#************************************************************************************************#
# Copyright (C) 2021 by Cadence Design Systems Inc	         	                         #
#************************************************************************************************#
#************************************************************************************************#
# IP               : cdn_sd1000_t16ffc_01_vc176_2xa1xd3xe2y2r                            	 #
# DESCRIPTION      : LEF file  									 #
# CREATED BY       : Sachin Nandurkar (sachinn@cadence.com)       				 #
# LAST CHANGED     : 20210527                                                                    #
# VERSION          : 102                                                                         #
# VERSION HISTORY  : 101 20191024 , File created				 		 #
# VERSION HISTORY  : 102 20210602 , Updated bump pin location				 	 #
# DISCLAIMER       : The lef parser used to verify the syntax of this file may have bugs. Please #
#                  : ensure that there are no problems while you read this file in your tool. 	 #
#************************************************************************************************#

VERSION 5.7 ;
BUSBITCHARS "[]" ;
DIVIDERCHAR "/" ;

SITE SITEOFcdn_sd1000_t16ffc_01_vc176_2xa1xd3xe2y2r
  CLASS CORE ;
  SYMMETRY X Y ;
  SIZE 540 BY 540 ;
END SITEOFcdn_sd1000_t16ffc_01_vc176_2xa1xd3xe2y2r

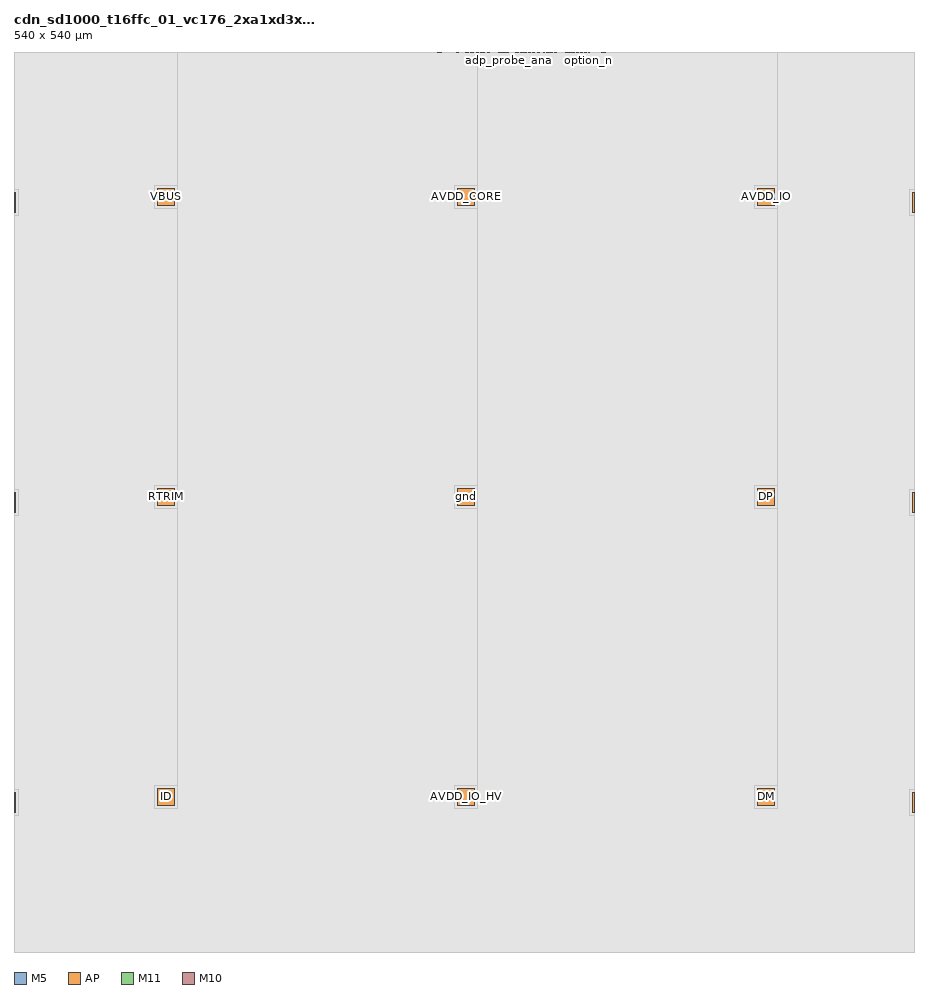
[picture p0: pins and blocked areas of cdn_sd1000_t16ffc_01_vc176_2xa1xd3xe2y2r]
MACRO cdn_sd1000_t16ffc_01_vc176_2xa1xd3xe2y2r
  CLASS BLOCK ;
  ORIGIN 0 0 ;
  FOREIGN cdn_sd1000_t16ffc_01_vc176_2xa1xd3xe2y2r 0 0 ;
  SIZE 540 BY 540 ;
  SYMMETRY X Y ;
  SITE SITEOFcdn_sd1000_t16ffc_01_vc176_2xa1xd3xe2y2r ;
  PIN tap_trst_n
    DIRECTION INPUT ;
    USE SIGNAL ;
    PORT
      LAYER M5 ;
        RECT 321.64 539.8 321.72 540 ;
    END
  END tap_trst_n
  PIN databus_reset
    DIRECTION INPUT ;
    USE SIGNAL ;
    PORT
      LAYER M5 ;
        RECT 305.88 539.8 305.96 540 ;
    END
  END databus_reset
  PIN hssi_tx_clockin
    DIRECTION INPUT ;
    USE SIGNAL ;
    PORT
      LAYER M5 ;
        RECT 265.72 539.8 265.8 540 ;
    END
  END hssi_tx_clockin
  PIN scan_sieclock
    DIRECTION INPUT ;
    USE SIGNAL ;
    PORT
      LAYER M5 ;
        RECT 266.68 539.8 266.76 540 ;
    END
  END scan_sieclock
  PIN psm_clock
    DIRECTION INPUT ;
    USE SIGNAL ;
    PORT
      LAYER M5 ;
        RECT 267.64 539.8 267.72 540 ;
    END
  END psm_clock
  PIN apb_pclk
    DIRECTION INPUT ;
    USE SIGNAL ;
    PORT
      LAYER M5 ;
        RECT 267.32 539.8 267.4 540 ;
    END
  END apb_pclk
  PIN scan_out[22]
    DIRECTION OUTPUT ;
    USE SIGNAL ;
    PORT
      LAYER M5 ;
        RECT 353.08 539.8 353.16 540 ;
    END
  END scan_out[22]
  PIN scan_out[33]
    DIRECTION OUTPUT ;
    USE SIGNAL ;
    PORT
      LAYER M5 ;
        RECT 354.84 539.8 354.92 540 ;
    END
  END scan_out[33]
  PIN scan_out[31]
    DIRECTION OUTPUT ;
    USE SIGNAL ;
    PORT
      LAYER M5 ;
        RECT 354.52 539.8 354.6 540 ;
    END
  END scan_out[31]
  PIN scan_out[29]
    DIRECTION OUTPUT ;
    USE SIGNAL ;
    PORT
      LAYER M5 ;
        RECT 354.2 539.8 354.28 540 ;
    END
  END scan_out[29]
  PIN scan_out[27]
    DIRECTION OUTPUT ;
    USE SIGNAL ;
    PORT
      LAYER M5 ;
        RECT 353.88 539.8 353.96 540 ;
    END
  END scan_out[27]
  PIN scan_out[25]
    DIRECTION OUTPUT ;
    USE SIGNAL ;
    PORT
      LAYER M5 ;
        RECT 353.56 539.8 353.64 540 ;
    END
  END scan_out[25]
  PIN scan_out[23]
    DIRECTION OUTPUT ;
    USE SIGNAL ;
    PORT
      LAYER M5 ;
        RECT 353.24 539.8 353.32 540 ;
    END
  END scan_out[23]
  PIN scan_out[20]
    DIRECTION OUTPUT ;
    USE SIGNAL ;
    PORT
      LAYER M5 ;
        RECT 352.76 539.8 352.84 540 ;
    END
  END scan_out[20]
  PIN scan_out[18]
    DIRECTION OUTPUT ;
    USE SIGNAL ;
    PORT
      LAYER M5 ;
        RECT 352.44 539.8 352.52 540 ;
    END
  END scan_out[18]
  PIN scan_in[18]
    DIRECTION INPUT ;
    USE SIGNAL ;
    PORT
      LAYER M5 ;
        RECT 279.32 539.8 279.4 540 ;
    END
  END scan_in[18]
  PIN scan_in[20]
    DIRECTION INPUT ;
    USE SIGNAL ;
    PORT
      LAYER M5 ;
        RECT 279.64 539.8 279.72 540 ;
    END
  END scan_in[20]
  PIN scan_in[22]
    DIRECTION INPUT ;
    USE SIGNAL ;
    PORT
      LAYER M5 ;
        RECT 279.96 539.8 280.04 540 ;
    END
  END scan_in[22]
  PIN adp_sense_ana
    DIRECTION OUTPUT ;
    USE SIGNAL ;
    PORT
      LAYER M5 ;
        RECT 296.52 539.8 296.6 540 ;
    END
  END adp_sense_ana
  PIN sessvld
    DIRECTION OUTPUT ;
    USE SIGNAL ;
    PORT
      LAYER M5 ;
        RECT 296.84 539.8 296.92 540 ;
    END
  END sessvld
  PIN iddig
    DIRECTION OUTPUT ;
    USE SIGNAL ;
    PORT
      LAYER M5 ;
        RECT 303.96 539.8 304.04 540 ;
    END
  END iddig
  PIN hssi_ded_ana
    DIRECTION OUTPUT ;
    USE SIGNAL ;
    PORT
      LAYER M5 ;
        RECT 304.12 539.8 304.2 540 ;
    END
  END hssi_ded_ana
  PIN hssi_squelch
    DIRECTION OUTPUT ;
    USE SIGNAL ;
    PORT
      LAYER M5 ;
        RECT 318.44 539.8 318.52 540 ;
    END
  END hssi_squelch
  PIN hssi_dataout[0]
    DIRECTION OUTPUT ;
    USE SIGNAL ;
    PORT
      LAYER M5 ;
        RECT 337.56 539.8 337.64 540 ;
    END
  END hssi_dataout[0]
  PIN hssi_dataout[2]
    DIRECTION OUTPUT ;
    USE SIGNAL ;
    PORT
      LAYER M5 ;
        RECT 337.88 539.8 337.96 540 ;
    END
  END hssi_dataout[2]
  PIN rx_rcv
    DIRECTION OUTPUT ;
    USE SIGNAL ;
    PORT
      LAYER M5 ;
        RECT 325.48 539.8 325.56 540 ;
    END
  END rx_rcv
  PIN rx_dm
    DIRECTION OUTPUT ;
    USE SIGNAL ;
    PORT
      LAYER M5 ;
        RECT 304.44 539.8 304.52 540 ;
    END
  END rx_dm
  PIN dataout[1]
    DIRECTION OUTPUT ;
    USE SIGNAL ;
    PORT
      LAYER M5 ;
        RECT 335.16 539.8 335.24 540 ;
    END
  END dataout[1]
  PIN datain[6]
    DIRECTION INPUT ;
    USE SIGNAL ;
    PORT
      LAYER M5 ;
        RECT 292.36 539.8 292.44 540 ;
    END
  END datain[6]
  PIN datain[8]
    DIRECTION INPUT ;
    USE SIGNAL ;
    PORT
      LAYER M5 ;
        RECT 292.68 539.8 292.76 540 ;
    END
  END datain[8]
  PIN dp_vdat_ref_comp_en
    DIRECTION INPUT ;
    USE SIGNAL ;
    PORT
      LAYER M5 ;
        RECT 310.84 539.8 310.92 540 ;
    END
  END dp_vdat_ref_comp_en
  PIN scan_in[34]
    DIRECTION INPUT ;
    USE SIGNAL ;
    PORT
      LAYER M5 ;
        RECT 281.88 539.8 281.96 540 ;
    END
  END scan_in[34]
  PIN usb2_phy_spare_out[7]
    DIRECTION OUTPUT ;
    USE SIGNAL ;
    PORT
      LAYER M5 ;
        RECT 340.6 539.8 340.68 540 ;
    END
  END usb2_phy_spare_out[7]
  PIN apb_pready
    DIRECTION OUTPUT ;
    USE SIGNAL ;
    PORT
      LAYER M5 ;
        RECT 306.2 539.8 306.28 540 ;
    END
  END apb_pready
  PIN usb2_phy_spare_out[1]
    DIRECTION OUTPUT ;
    USE SIGNAL ;
    PORT
      LAYER M5 ;
        RECT 339.64 539.8 339.72 540 ;
    END
  END usb2_phy_spare_out[1]
  PIN usb2_phy_spare_out[5]
    DIRECTION OUTPUT ;
    USE SIGNAL ;
    PORT
      LAYER M5 ;
        RECT 340.28 539.8 340.36 540 ;
    END
  END usb2_phy_spare_out[5]
  PIN dm_vdat_ref_comp_en
    DIRECTION INPUT ;
    USE SIGNAL ;
    PORT
      LAYER M5 ;
        RECT 324.36 539.8 324.44 540 ;
    END
  END dm_vdat_ref_comp_en
  PIN usb2_phy_spare_out[3]
    DIRECTION OUTPUT ;
    USE SIGNAL ;
    PORT
      LAYER M5 ;
        RECT 339.96 539.8 340.04 540 ;
    END
  END usb2_phy_spare_out[3]
  PIN scan_in[17]
    DIRECTION INPUT ;
    USE SIGNAL ;
    PORT
      LAYER M5 ;
        RECT 279.16 539.8 279.24 540 ;
    END
  END scan_in[17]
  PIN bist_mode_sel[0]
    DIRECTION INPUT ;
    USE SIGNAL ;
    PORT
      LAYER M5 ;
        RECT 333.08 539.8 333.16 540 ;
    END
  END bist_mode_sel[0]
  PIN scan_in[14]
    DIRECTION INPUT ;
    USE SIGNAL ;
    PORT
      LAYER M5 ;
        RECT 278.68 539.8 278.76 540 ;
    END
  END scan_in[14]
  PIN scan_en
    DIRECTION INPUT ;
    USE SIGNAL ;
    PORT
      LAYER M5 ;
        RECT 309.4 539.8 309.48 540 ;
    END
  END scan_en
  PIN dataout[11]
    DIRECTION OUTPUT ;
    USE SIGNAL ;
    PORT
      LAYER M5 ;
        RECT 336.76 539.8 336.84 540 ;
    END
  END dataout[11]
  PIN dataout[9]
    DIRECTION OUTPUT ;
    USE SIGNAL ;
    PORT
      LAYER M5 ;
        RECT 336.44 539.8 336.52 540 ;
    END
  END dataout[9]
  PIN apb_presetn
    DIRECTION INPUT ;
    USE SIGNAL ;
    PORT
      LAYER M5 ;
        RECT 321.48 539.8 321.56 540 ;
    END
  END apb_presetn
  PIN iddq_mode
    DIRECTION INPUT ;
    USE SIGNAL ;
    PORT
      LAYER M5 ;
        RECT 310.04 539.8 310.12 540 ;
    END
  END iddq_mode
  PIN scan_clock
    DIRECTION INPUT ;
    USE SIGNAL ;
    PORT
      LAYER M5 ;
        RECT 267.96 539.8 268.04 540 ;
    END
  END scan_clock
  PIN tx_se0
    DIRECTION INPUT ;
    USE SIGNAL ;
    PORT
      LAYER M5 ;
        RECT 323.24 539.8 323.32 540 ;
    END
  END tx_se0
  PIN dataout[13]
    DIRECTION OUTPUT ;
    USE SIGNAL ;
    PORT
      LAYER M5 ;
        RECT 337.08 539.8 337.16 540 ;
    END
  END dataout[13]
  PIN dataout[15]
    DIRECTION OUTPUT ;
    USE SIGNAL ;
    PORT
      LAYER M5 ;
        RECT 337.4 539.8 337.48 540 ;
    END
  END dataout[15]
  PIN rxvalid
    DIRECTION OUTPUT ;
    USE SIGNAL ;
    PORT
      LAYER M5 ;
        RECT 319.24 539.8 319.32 540 ;
    END
  END rxvalid
  PIN rxactive
    DIRECTION OUTPUT ;
    USE SIGNAL ;
    PORT
      LAYER M5 ;
        RECT 307.16 539.8 307.24 540 ;
    END
  END rxactive
  PIN linestate[0]
    DIRECTION OUTPUT ;
    USE SIGNAL ;
    PORT
      LAYER M5 ;
        RECT 305.4 539.8 305.48 540 ;
    END
  END linestate[0]
  PIN hostdisconnect
    DIRECTION OUTPUT ;
    USE SIGNAL ;
    PORT
      LAYER M5 ;
        RECT 305.72 539.8 305.8 540 ;
    END
  END hostdisconnect
  PIN scan_out[1]
    DIRECTION OUTPUT ;
    USE SIGNAL ;
    PORT
      LAYER M5 ;
        RECT 340.92 539.8 341 540 ;
    END
  END scan_out[1]
  PIN scan_out[3]
    DIRECTION OUTPUT ;
    USE SIGNAL ;
    PORT
      LAYER M5 ;
        RECT 341.24 539.8 341.32 540 ;
    END
  END scan_out[3]
  PIN scan_out[5]
    DIRECTION OUTPUT ;
    USE SIGNAL ;
    PORT
      LAYER M5 ;
        RECT 341.56 539.8 341.64 540 ;
    END
  END scan_out[5]
  PIN scan_out[7]
    DIRECTION OUTPUT ;
    USE SIGNAL ;
    PORT
      LAYER M5 ;
        RECT 341.88 539.8 341.96 540 ;
    END
  END scan_out[7]
  PIN scan_out[9]
    DIRECTION OUTPUT ;
    USE SIGNAL ;
    PORT
      LAYER M5 ;
        RECT 342.2 539.8 342.28 540 ;
    END
  END scan_out[9]
  PIN scan_out[11]
    DIRECTION OUTPUT ;
    USE SIGNAL ;
    PORT
      LAYER M5 ;
        RECT 342.52 539.8 342.6 540 ;
    END
  END scan_out[11]
  PIN scan_out[13]
    DIRECTION OUTPUT ;
    USE SIGNAL ;
    PORT
      LAYER M5 ;
        RECT 342.84 539.8 342.92 540 ;
    END
  END scan_out[13]
  PIN hssi_rx_clockout
    DIRECTION OUTPUT ;
    USE SIGNAL ;
    PORT
      LAYER M5 ;
        RECT 269.24 539.8 269.32 540 ;
    END
  END hssi_rx_clockout
  PIN pll_clockout
    DIRECTION OUTPUT ;
    USE SIGNAL ;
    PORT
      LAYER M5 ;
        RECT 268.92 539.8 269 540 ;
    END
  END pll_clockout
  PIN scan_ats_sieclock
    DIRECTION OUTPUT ;
    USE SIGNAL ;
    PORT
      LAYER M5 ;
        RECT 265.08 539.8 265.16 540 ;
    END
  END scan_ats_sieclock
  PIN tx_dat
    DIRECTION INPUT ;
    USE SIGNAL ;
    PORT
      LAYER M5 ;
        RECT 319.4 539.8 319.48 540 ;
    END
  END tx_dat
  PIN refclock
    DIRECTION INPUT ;
    USE SIGNAL ;
    PORT
      LAYER M5 ;
        RECT 266.04 539.8 266.12 540 ;
    END
  END refclock
  PIN tap_tck
    DIRECTION INPUT ;
    USE SIGNAL ;
    PORT
      LAYER M5 ;
        RECT 306.04 539.8 306.12 540 ;
    END
  END tap_tck
  PIN scan_hsclock
    DIRECTION INPUT ;
    USE SIGNAL ;
    PORT
      LAYER M5 ;
        RECT 267 539.8 267.08 540 ;
    END
  END scan_hsclock
  PIN datain[0]
    DIRECTION INPUT ;
    USE SIGNAL ;
    PORT
      LAYER M5 ;
        RECT 291.4 539.8 291.48 540 ;
    END
  END datain[0]
  PIN datain[2]
    DIRECTION INPUT ;
    USE SIGNAL ;
    PORT
      LAYER M5 ;
        RECT 291.72 539.8 291.8 540 ;
    END
  END datain[2]
  PIN datain[4]
    DIRECTION INPUT ;
    USE SIGNAL ;
    PORT
      LAYER M5 ;
        RECT 292.04 539.8 292.12 540 ;
    END
  END datain[4]
  PIN bist_complete
    DIRECTION OUTPUT ;
    USE SIGNAL ;
    PORT
      LAYER M5 ;
        RECT 295.72 539.8 295.8 540 ;
    END
  END bist_complete
  PIN rid_float_comp_sts
    DIRECTION OUTPUT ;
    USE SIGNAL ;
    PORT
      LAYER M5 ;
        RECT 295.88 539.8 295.96 540 ;
    END
  END rid_float_comp_sts
  PIN rid_b_comp_sts
    DIRECTION OUTPUT ;
    USE SIGNAL ;
    PORT
      LAYER M5 ;
        RECT 306.52 539.8 306.6 540 ;
    END
  END rid_b_comp_sts
  PIN dp_vdat_ref_comp_sts
    DIRECTION OUTPUT ;
    USE SIGNAL ;
    PORT
      LAYER M5 ;
        RECT 296.2 539.8 296.28 540 ;
    END
  END dp_vdat_ref_comp_sts
  PIN dm_vdat_ref_comp_sts
    DIRECTION OUTPUT ;
    USE SIGNAL ;
    PORT
      LAYER M5 ;
        RECT 296.36 539.8 296.44 540 ;
    END
  END dm_vdat_ref_comp_sts
  PIN pll_clk_sel[1]
    DIRECTION INPUT ;
    USE SIGNAL ;
    PORT
      LAYER M5 ;
        RECT 266.36 539.8 266.44 540 ;
    END
  END pll_clk_sel[1]
  PIN option_cv
    DIRECTION INPUT ;
    USE SIGNAL ;
    PORT
      LAYER M5 ;
        RECT 345.08 539.8 345.16 540 ;
    END
  END option_cv
  PIN tap_tms
    DIRECTION INPUT ;
    USE SIGNAL ;
    PORT
      LAYER M5 ;
        RECT 309.72 539.8 309.8 540 ;
    END
  END tap_tms
  PIN apb_pwdata[0]
    DIRECTION INPUT ;
    USE SIGNAL ;
    PORT
      LAYER M5 ;
        RECT 333.72 539.8 333.8 540 ;
    END
  END apb_pwdata[0]
  PIN apb_pwdata[2]
    DIRECTION INPUT ;
    USE SIGNAL ;
    PORT
      LAYER M5 ;
        RECT 334.04 539.8 334.12 540 ;
    END
  END apb_pwdata[2]
  PIN apb_pwdata[4]
    DIRECTION INPUT ;
    USE SIGNAL ;
    PORT
      LAYER M5 ;
        RECT 334.36 539.8 334.44 540 ;
    END
  END apb_pwdata[4]
  PIN apb_pwdata[6]
    DIRECTION INPUT ;
    USE SIGNAL ;
    PORT
      LAYER M5 ;
        RECT 334.68 539.8 334.76 540 ;
    END
  END apb_pwdata[6]
  PIN apb_paddr[0]
    DIRECTION INPUT ;
    USE SIGNAL ;
    PORT
      LAYER M5 ;
        RECT 332.92 539.8 333 540 ;
    END
  END apb_paddr[0]
  PIN scan_out[16]
    DIRECTION OUTPUT ;
    USE SIGNAL ;
    PORT
      LAYER M5 ;
        RECT 343.32 539.8 343.4 540 ;
    END
  END scan_out[16]
  PIN datain[14]
    DIRECTION INPUT ;
    USE SIGNAL ;
    PORT
      LAYER M5 ;
        RECT 293.64 539.8 293.72 540 ;
    END
  END datain[14]
  PIN usb2_phy_spare_out[6]
    DIRECTION OUTPUT ;
    USE SIGNAL ;
    PORT
      LAYER M5 ;
        RECT 340.44 539.8 340.52 540 ;
    END
  END usb2_phy_spare_out[6]
  PIN bist_error_count[0]
    DIRECTION OUTPUT ;
    USE SIGNAL ;
    PORT
      LAYER M5 ;
        RECT 338.2 539.8 338.28 540 ;
    END
  END bist_error_count[0]
  PIN bist_error_count[2]
    DIRECTION OUTPUT ;
    USE SIGNAL ;
    PORT
      LAYER M5 ;
        RECT 338.52 539.8 338.6 540 ;
    END
  END bist_error_count[2]
  PIN bist_error_count[4]
    DIRECTION OUTPUT ;
    USE SIGNAL ;
    PORT
      LAYER M5 ;
        RECT 338.84 539.8 338.92 540 ;
    END
  END bist_error_count[4]
  PIN bist_error_count[6]
    DIRECTION OUTPUT ;
    USE SIGNAL ;
    PORT
      LAYER M5 ;
        RECT 339.16 539.8 339.24 540 ;
    END
  END bist_error_count[6]
  PIN bist_error
    DIRECTION OUTPUT ;
    USE SIGNAL ;
    PORT
      LAYER M5 ;
        RECT 310.52 539.8 310.6 540 ;
    END
  END bist_error
  PIN rid_gnd_comp_sts
    DIRECTION OUTPUT ;
    USE SIGNAL ;
    PORT
      LAYER M5 ;
        RECT 306.36 539.8 306.44 540 ;
    END
  END rid_gnd_comp_sts
  PIN rid_c_comp_sts
    DIRECTION OUTPUT ;
    USE SIGNAL ;
    PORT
      LAYER M5 ;
        RECT 325.64 539.8 325.72 540 ;
    END
  END rid_c_comp_sts
  PIN rid_a_comp_sts
    DIRECTION OUTPUT ;
    USE SIGNAL ;
    PORT
      LAYER M5 ;
        RECT 296.04 539.8 296.12 540 ;
    END
  END rid_a_comp_sts
  PIN dm_vlgc_comp_sts
    DIRECTION OUTPUT ;
    USE SIGNAL ;
    PORT
      LAYER M5 ;
        RECT 306.68 539.8 306.76 540 ;
    END
  END dm_vlgc_comp_sts
  PIN dcd_comp_sts
    DIRECTION OUTPUT ;
    USE SIGNAL ;
    PORT
      LAYER M5 ;
        RECT 306.84 539.8 306.92 540 ;
    END
  END dcd_comp_sts
  PIN adp_probe_ana
    DIRECTION OUTPUT ;
    USE SIGNAL ;
    PORT
      LAYER M5 ;
        RECT 296.68 539.8 296.76 540 ;
    END
  END adp_probe_ana
  PIN vbusvalid
    DIRECTION OUTPUT ;
    USE SIGNAL ;
    PORT
      LAYER M5 ;
        RECT 297 539.8 297.08 540 ;
    END
  END vbusvalid
  PIN hssi_chirp_data
    DIRECTION OUTPUT ;
    USE SIGNAL ;
    PORT
      LAYER M5 ;
        RECT 317.96 539.8 318.04 540 ;
    END
  END hssi_chirp_data
  PIN hssi_rxerror
    DIRECTION OUTPUT ;
    USE SIGNAL ;
    PORT
      LAYER M5 ;
        RECT 307 539.8 307.08 540 ;
    END
  END hssi_rxerror
  PIN hssi_rxvalid
    DIRECTION OUTPUT ;
    USE SIGNAL ;
    PORT
      LAYER M5 ;
        RECT 304.28 539.8 304.36 540 ;
    END
  END hssi_rxvalid
  PIN hssi_dataout[1]
    DIRECTION OUTPUT ;
    USE SIGNAL ;
    PORT
      LAYER M5 ;
        RECT 337.72 539.8 337.8 540 ;
    END
  END hssi_dataout[1]
  PIN hssi_dataout[3]
    DIRECTION OUTPUT ;
    USE SIGNAL ;
    PORT
      LAYER M5 ;
        RECT 338.04 539.8 338.12 540 ;
    END
  END hssi_dataout[3]
  PIN rx_dp
    DIRECTION OUTPUT ;
    USE SIGNAL ;
    PORT
      LAYER M5 ;
        RECT 318.92 539.8 319 540 ;
    END
  END rx_dp
  PIN dataout[0]
    DIRECTION OUTPUT ;
    USE SIGNAL ;
    PORT
      LAYER M5 ;
        RECT 335 539.8 335.08 540 ;
    END
  END dataout[0]
  PIN dataout[2]
    DIRECTION OUTPUT ;
    USE SIGNAL ;
    PORT
      LAYER M5 ;
        RECT 335.32 539.8 335.4 540 ;
    END
  END dataout[2]
  PIN dataout[4]
    DIRECTION OUTPUT ;
    USE SIGNAL ;
    PORT
      LAYER M5 ;
        RECT 335.64 539.8 335.72 540 ;
    END
  END dataout[4]
  PIN dataout[6]
    DIRECTION OUTPUT ;
    USE SIGNAL ;
    PORT
      LAYER M5 ;
        RECT 335.96 539.8 336.04 540 ;
    END
  END dataout[6]
  PIN dataout[8]
    DIRECTION OUTPUT ;
    USE SIGNAL ;
    PORT
      LAYER M5 ;
        RECT 336.28 539.8 336.36 540 ;
    END
  END dataout[8]
  PIN dataout[10]
    DIRECTION OUTPUT ;
    USE SIGNAL ;
    PORT
      LAYER M5 ;
        RECT 336.6 539.8 336.68 540 ;
    END
  END dataout[10]
  PIN dataout[12]
    DIRECTION OUTPUT ;
    USE SIGNAL ;
    PORT
      LAYER M5 ;
        RECT 336.92 539.8 337 540 ;
    END
  END dataout[12]
  PIN dataout[14]
    DIRECTION OUTPUT ;
    USE SIGNAL ;
    PORT
      LAYER M5 ;
        RECT 337.24 539.8 337.32 540 ;
    END
  END dataout[14]
  PIN rxvalidh
    DIRECTION OUTPUT ;
    USE SIGNAL ;
    PORT
      LAYER M5 ;
        RECT 325.32 539.8 325.4 540 ;
    END
  END rxvalidh
  PIN rxerror
    DIRECTION OUTPUT ;
    USE SIGNAL ;
    PORT
      LAYER M5 ;
        RECT 304.92 539.8 305 540 ;
    END
  END rxerror
  PIN txready
    DIRECTION OUTPUT ;
    USE SIGNAL ;
    PORT
      LAYER M5 ;
        RECT 305.24 539.8 305.32 540 ;
    END
  END txready
  PIN linestate[1]
    DIRECTION OUTPUT ;
    USE SIGNAL ;
    PORT
      LAYER M5 ;
        RECT 305.56 539.8 305.64 540 ;
    END
  END linestate[1]
  PIN scan_out[0]
    DIRECTION OUTPUT ;
    USE SIGNAL ;
    PORT
      LAYER M5 ;
        RECT 340.76 539.8 340.84 540 ;
    END
  END scan_out[0]
  PIN scan_out[2]
    DIRECTION OUTPUT ;
    USE SIGNAL ;
    PORT
      LAYER M5 ;
        RECT 341.08 539.8 341.16 540 ;
    END
  END scan_out[2]
  PIN scan_out[4]
    DIRECTION OUTPUT ;
    USE SIGNAL ;
    PORT
      LAYER M5 ;
        RECT 341.4 539.8 341.48 540 ;
    END
  END scan_out[4]
  PIN scan_out[6]
    DIRECTION OUTPUT ;
    USE SIGNAL ;
    PORT
      LAYER M5 ;
        RECT 341.72 539.8 341.8 540 ;
    END
  END scan_out[6]
  PIN scan_out[8]
    DIRECTION OUTPUT ;
    USE SIGNAL ;
    PORT
      LAYER M5 ;
        RECT 342.04 539.8 342.12 540 ;
    END
  END scan_out[8]
  PIN scan_out[10]
    DIRECTION OUTPUT ;
    USE SIGNAL ;
    PORT
      LAYER M5 ;
        RECT 342.36 539.8 342.44 540 ;
    END
  END scan_out[10]
  PIN scan_out[12]
    DIRECTION OUTPUT ;
    USE SIGNAL ;
    PORT
      LAYER M5 ;
        RECT 342.68 539.8 342.76 540 ;
    END
  END scan_out[12]
  PIN scan_out[14]
    DIRECTION OUTPUT ;
    USE SIGNAL ;
    PORT
      LAYER M5 ;
        RECT 343 539.8 343.08 540 ;
    END
  END scan_out[14]
  PIN hssi_tx_clockout
    DIRECTION OUTPUT ;
    USE SIGNAL ;
    PORT
      LAYER M5 ;
        RECT 264.76 539.8 264.84 540 ;
    END
  END hssi_tx_clockout
  PIN sieclock
    DIRECTION OUTPUT ;
    USE SIGNAL ;
    PORT
      LAYER M5 ;
        RECT 268.6 539.8 268.68 540 ;
    END
  END sieclock
  PIN scan_ats_hsclock
    DIRECTION OUTPUT ;
    USE SIGNAL ;
    PORT
      LAYER M5 ;
        RECT 265.4 539.8 265.48 540 ;
    END
  END scan_ats_hsclock
  PIN option_n
    DIRECTION INPUT ;
    USE SIGNAL ;
    PORT
      LAYER M5 ;
        RECT 344.92 539.8 345 540 ;
    END
  END option_n
  PIN tap_tdi
    DIRECTION INPUT ;
    USE SIGNAL ;
    PORT
      LAYER M5 ;
        RECT 307.32 539.8 307.4 540 ;
    END
  END tap_tdi
  PIN apb_pwdata[1]
    DIRECTION INPUT ;
    USE SIGNAL ;
    PORT
      LAYER M5 ;
        RECT 333.88 539.8 333.96 540 ;
    END
  END apb_pwdata[1]
  PIN apb_pwdata[3]
    DIRECTION INPUT ;
    USE SIGNAL ;
    PORT
      LAYER M5 ;
        RECT 334.2 539.8 334.28 540 ;
    END
  END apb_pwdata[3]
  PIN apb_pwdata[5]
    DIRECTION INPUT ;
    USE SIGNAL ;
    PORT
      LAYER M5 ;
        RECT 334.52 539.8 334.6 540 ;
    END
  END apb_pwdata[5]
  PIN apb_pwdata[7]
    DIRECTION INPUT ;
    USE SIGNAL ;
    PORT
      LAYER M5 ;
        RECT 334.84 539.8 334.92 540 ;
    END
  END apb_pwdata[7]
  PIN apb_paddr[1]
    DIRECTION INPUT ;
    USE SIGNAL ;
    PORT
      LAYER M5 ;
        RECT 332.76 539.8 332.84 540 ;
    END
  END apb_paddr[1]
  PIN apb_paddr[2]
    DIRECTION INPUT ;
    USE SIGNAL ;
    PORT
      LAYER M5 ;
        RECT 332.6 539.8 332.68 540 ;
    END
  END apb_paddr[2]
  PIN scan_in[15]
    DIRECTION INPUT ;
    USE SIGNAL ;
    PORT
      LAYER M5 ;
        RECT 278.84 539.8 278.92 540 ;
    END
  END scan_in[15]
  PIN scan_en_cg
    DIRECTION INPUT ;
    USE SIGNAL ;
    PORT
      LAYER M5 ;
        RECT 282.04 539.8 282.12 540 ;
    END
  END scan_en_cg
  PIN tap_tdoen
    DIRECTION OUTPUT ;
    USE SIGNAL ;
    PORT
      LAYER M5 ;
        RECT 295.24 539.8 295.32 540 ;
    END
  END tap_tdoen
  PIN apb_prdata[0]
    DIRECTION OUTPUT ;
    USE SIGNAL ;
    PORT
      LAYER M5 ;
        RECT 343.48 539.8 343.56 540 ;
    END
  END apb_prdata[0]
  PIN apb_prdata[2]
    DIRECTION OUTPUT ;
    USE SIGNAL ;
    PORT
      LAYER M5 ;
        RECT 343.8 539.8 343.88 540 ;
    END
  END apb_prdata[2]
  PIN apb_prdata[4]
    DIRECTION OUTPUT ;
    USE SIGNAL ;
    PORT
      LAYER M5 ;
        RECT 344.12 539.8 344.2 540 ;
    END
  END apb_prdata[4]
  PIN apb_prdata[6]
    DIRECTION OUTPUT ;
    USE SIGNAL ;
    PORT
      LAYER M5 ;
        RECT 344.44 539.8 344.52 540 ;
    END
  END apb_prdata[6]
  PIN apb_paddr[4]
    DIRECTION INPUT ;
    USE SIGNAL ;
    PORT
      LAYER M5 ;
        RECT 332.28 539.8 332.36 540 ;
    END
  END apb_paddr[4]
  PIN apb_paddr[6]
    DIRECTION INPUT ;
    USE SIGNAL ;
    PORT
      LAYER M5 ;
        RECT 331.96 539.8 332.04 540 ;
    END
  END apb_paddr[6]
  PIN usb2_phy_irq
    DIRECTION OUTPUT ;
    USE SIGNAL ;
    PORT
      LAYER M5 ;
        RECT 345.24 539.8 345.32 540 ;
    END
  END usb2_phy_irq
  PIN apb_penable
    DIRECTION INPUT ;
    USE SIGNAL ;
    PORT
      LAYER M5 ;
        RECT 325.16 539.8 325.24 540 ;
    END
  END apb_penable
  PIN usb2_phy_spare_in[0]
    DIRECTION INPUT ;
    USE SIGNAL ;
    PORT
      LAYER M5 ;
        RECT 293.96 539.8 294.04 540 ;
    END
  END usb2_phy_spare_in[0]
  PIN usb2_phy_spare_in[2]
    DIRECTION INPUT ;
    USE SIGNAL ;
    PORT
      LAYER M5 ;
        RECT 294.28 539.8 294.36 540 ;
    END
  END usb2_phy_spare_in[2]
  PIN usb2_phy_spare_in[4]
    DIRECTION INPUT ;
    USE SIGNAL ;
    PORT
      LAYER M5 ;
        RECT 294.6 539.8 294.68 540 ;
    END
  END usb2_phy_spare_in[4]
  PIN usb2_phy_spare_in[6]
    DIRECTION INPUT ;
    USE SIGNAL ;
    PORT
      LAYER M5 ;
        RECT 294.92 539.8 295 540 ;
    END
  END usb2_phy_spare_in[6]
  PIN loopback[0]
    DIRECTION INPUT ;
    USE SIGNAL ;
    PORT
      LAYER M5 ;
        RECT 325 539.8 325.08 540 ;
    END
  END loopback[0]
  PIN bist_on
    DIRECTION INPUT ;
    USE SIGNAL ;
    PORT
      LAYER M5 ;
        RECT 324.68 539.8 324.76 540 ;
    END
  END bist_on
  PIN bist_mode_sel[1]
    DIRECTION INPUT ;
    USE SIGNAL ;
    PORT
      LAYER M5 ;
        RECT 333.24 539.8 333.32 540 ;
    END
  END bist_mode_sel[1]
  PIN bist_mode_sel[3]
    DIRECTION INPUT ;
    USE SIGNAL ;
    PORT
      LAYER M5 ;
        RECT 333.56 539.8 333.64 540 ;
    END
  END bist_mode_sel[3]
  PIN pll_bypass_mode
    DIRECTION INPUT ;
    USE SIGNAL ;
    PORT
      LAYER M5 ;
        RECT 307.64 539.8 307.72 540 ;
    END
  END pll_bypass_mode
  PIN vdp_src_en
    DIRECTION INPUT ;
    USE SIGNAL ;
    PORT
      LAYER M5 ;
        RECT 307.96 539.8 308.04 540 ;
    END
  END vdp_src_en
  PIN rid_nonfloat_comp_en
    DIRECTION INPUT ;
    USE SIGNAL ;
    PORT
      LAYER M5 ;
        RECT 324.52 539.8 324.6 540 ;
    END
  END rid_nonfloat_comp_en
  PIN idp_src_en
    DIRECTION INPUT ;
    USE SIGNAL ;
    PORT
      LAYER M5 ;
        RECT 295.56 539.8 295.64 540 ;
    END
  END idp_src_en
  PIN idm_sink_en
    DIRECTION INPUT ;
    USE SIGNAL ;
    PORT
      LAYER M5 ;
        RECT 308.12 539.8 308.2 540 ;
    END
  END idm_sink_en
  PIN dm_vlgc_comp_en
    DIRECTION INPUT ;
    USE SIGNAL ;
    PORT
      LAYER M5 ;
        RECT 311 539.8 311.08 540 ;
    END
  END dm_vlgc_comp_en
  PIN bc_en
    DIRECTION INPUT ;
    USE SIGNAL ;
    PORT
      LAYER M5 ;
        RECT 324.2 539.8 324.28 540 ;
    END
  END bc_en
  PIN adp_sink_current_en
    DIRECTION INPUT ;
    USE SIGNAL ;
    PORT
      LAYER M5 ;
        RECT 311.32 539.8 311.4 540 ;
    END
  END adp_sink_current_en
  PIN adp_en
    DIRECTION INPUT ;
    USE SIGNAL ;
    PORT
      LAYER M5 ;
        RECT 311.64 539.8 311.72 540 ;
    END
  END adp_en
  PIN idpullup
    DIRECTION INPUT ;
    USE SIGNAL ;
    PORT
      LAYER M5 ;
        RECT 308.28 539.8 308.36 540 ;
    END
  END idpullup
  PIN vbus_sel[1]
    DIRECTION INPUT ;
    USE SIGNAL ;
    PORT
      LAYER M5 ;
        RECT 321.32 539.8 321.4 540 ;
    END
  END vbus_sel[1]
  PIN pllrefsel[1]
    DIRECTION INPUT ;
    USE SIGNAL ;
    PORT
      LAYER M5 ;
        RECT 321.8 539.8 321.88 540 ;
    END
  END pllrefsel[1]
  PIN pllrefsel[3]
    DIRECTION INPUT ;
    USE SIGNAL ;
    PORT
      LAYER M5 ;
        RECT 322.28 539.8 322.36 540 ;
    END
  END pllrefsel[3]
  PIN pll_standalone
    DIRECTION INPUT ;
    USE SIGNAL ;
    PORT
      LAYER M5 ;
        RECT 308.44 539.8 308.52 540 ;
    END
  END pll_standalone
  PIN pll_clk_sel[0]
    DIRECTION INPUT ;
    USE SIGNAL ;
    PORT
      LAYER M5 ;
        RECT 268.28 539.8 268.36 540 ;
    END
  END pll_clk_sel[0]
  PIN usb2_phy_arch[0]
    DIRECTION INPUT ;
    USE SIGNAL ;
    PORT
      LAYER M5 ;
        RECT 318.28 539.8 318.36 540 ;
    END
  END usb2_phy_arch[0]
  PIN pso_disable_sel[0]
    DIRECTION INPUT ;
    USE SIGNAL ;
    PORT
      LAYER M5 ;
        RECT 304.6 539.8 304.68 540 ;
    END
  END pso_disable_sel[0]
  PIN pso_disable
    DIRECTION INPUT ;
    USE SIGNAL ;
    PORT
      LAYER M5 ;
        RECT 318.6 539.8 318.68 540 ;
    END
  END pso_disable
  PIN hssi_tx_enable
    DIRECTION INPUT ;
    USE SIGNAL ;
    PORT
      LAYER M5 ;
        RECT 318.76 539.8 318.84 540 ;
    END
  END hssi_tx_enable
  PIN hssi_txvalid[1]
    DIRECTION INPUT ;
    USE SIGNAL ;
    PORT
      LAYER M5 ;
        RECT 323.72 539.8 323.8 540 ;
    END
  END hssi_txvalid[1]
  PIN hssi_datain[1]
    DIRECTION INPUT ;
    USE SIGNAL ;
    PORT
      LAYER M5 ;
        RECT 291.08 539.8 291.16 540 ;
    END
  END hssi_datain[1]
  PIN idle_rpu_enable
    DIRECTION INPUT ;
    USE SIGNAL ;
    PORT
      LAYER M5 ;
        RECT 323.4 539.8 323.48 540 ;
    END
  END idle_rpu_enable
  PIN tx_enable_n
    DIRECTION INPUT ;
    USE SIGNAL ;
    PORT
      LAYER M5 ;
        RECT 305.08 539.8 305.16 540 ;
    END
  END tx_enable_n
  PIN fslsserialmode
    DIRECTION INPUT ;
    USE SIGNAL ;
    PORT
      LAYER M5 ;
        RECT 308.6 539.8 308.68 540 ;
    END
  END fslsserialmode
  PIN datain[1]
    DIRECTION INPUT ;
    USE SIGNAL ;
    PORT
      LAYER M5 ;
        RECT 291.56 539.8 291.64 540 ;
    END
  END datain[1]
  PIN datain[3]
    DIRECTION INPUT ;
    USE SIGNAL ;
    PORT
      LAYER M5 ;
        RECT 291.88 539.8 291.96 540 ;
    END
  END datain[3]
  PIN datain[5]
    DIRECTION INPUT ;
    USE SIGNAL ;
    PORT
      LAYER M5 ;
        RECT 292.2 539.8 292.28 540 ;
    END
  END datain[5]
  PIN VBUS
    DIRECTION INOUT ;
    USE ANALOG ;
    PORT
      CLASS BUMP ;
      LAYER AP ;
        RECT 86.269 448.2 96.269 458.2 ;
    END
  END VBUS
  PIN datain[7]
    DIRECTION INPUT ;
    USE SIGNAL ;
    PORT
      LAYER M5 ;
        RECT 292.52 539.8 292.6 540 ;
    END
  END datain[7]
  PIN datain[9]
    DIRECTION INPUT ;
    USE SIGNAL ;
    PORT
      LAYER M5 ;
        RECT 292.84 539.8 292.92 540 ;
    END
  END datain[9]
  PIN datain[11]
    DIRECTION INPUT ;
    USE SIGNAL ;
    PORT
      LAYER M5 ;
        RECT 293.16 539.8 293.24 540 ;
    END
  END datain[11]
  PIN gnd
    DIRECTION INOUT ;
    USE GROUND ;
    PORT
      CLASS BUMP ;
      LAYER AP ;
        RECT 266.269 268.2 276.269 278.2 ;
    END
    PORT
      LAYER M11 ;
        RECT 253.841 539.8 256.341 540 ;
    END
    PORT
      LAYER M10 ;
        RECT 253.841 539.8 256.341 540 ;
    END
    PORT
      LAYER M11 ;
        RECT 271 539.8 272.49 540 ;
    END
    PORT
      LAYER M10 ;
        RECT 271 539.8 272.49 540 ;
    END
    PORT
      LAYER M11 ;
        RECT 284.09 539.8 285.58 540 ;
    END
    PORT
      LAYER M10 ;
        RECT 284.09 539.8 285.58 540 ;
    END
    PORT
      LAYER M11 ;
        RECT 294.09 539.8 295.58 540 ;
    END
    PORT
      LAYER M10 ;
        RECT 294.09 539.8 295.58 540 ;
    END
    PORT
      LAYER M11 ;
        RECT 304.092 539.8 305.582 540 ;
    END
    PORT
      LAYER M10 ;
        RECT 304.092 539.8 305.582 540 ;
    END
    PORT
      LAYER M11 ;
        RECT 314.09 539.8 315.58 540 ;
    END
    PORT
      LAYER M10 ;
        RECT 314.09 539.8 315.58 540 ;
    END
    PORT
      LAYER M11 ;
        RECT 324.091 539.8 325.581 540 ;
    END
    PORT
      LAYER M10 ;
        RECT 324.091 539.8 325.581 540 ;
    END
    PORT
      LAYER M11 ;
        RECT 334.09 539.8 335.58 540 ;
    END
    PORT
      LAYER M10 ;
        RECT 334.09 539.8 335.58 540 ;
    END
    PORT
      LAYER M11 ;
        RECT 352.341 539.8 354.841 540 ;
    END
    PORT
      LAYER M10 ;
        RECT 352.341 539.8 354.841 540 ;
    END
    PORT
      LAYER AP ;
        RECT 0 443.976 1 455.976 ;
    END
    PORT
      LAYER AP ;
        RECT 0 263.976 1 275.976 ;
    END
    PORT
      LAYER AP ;
        RECT 0 83.976 1 95.976 ;
    END
    PORT
      LAYER AP ;
        RECT 539 443.976 540 455.976 ;
    END
    PORT
      LAYER AP ;
        RECT 539 263.976 540 275.976 ;
    END
    PORT
      LAYER AP ;
        RECT 539 83.976 540 95.976 ;
    END
  END gnd
  PIN datain[13]
    DIRECTION INPUT ;
    USE SIGNAL ;
    PORT
      LAYER M5 ;
        RECT 293.48 539.8 293.56 540 ;
    END
  END datain[13]
  PIN datain[15]
    DIRECTION INPUT ;
    USE SIGNAL ;
    PORT
      LAYER M5 ;
        RECT 293.8 539.8 293.88 540 ;
    END
  END datain[15]
  PIN txvalid
    DIRECTION INPUT ;
    USE SIGNAL ;
    PORT
      LAYER M5 ;
        RECT 322.76 539.8 322.84 540 ;
    END
  END txvalid
  PIN AVDD_IO
    DIRECTION INOUT ;
    USE POWER ;
    PORT
      CLASS BUMP ;
      LAYER AP ;
        RECT 446.269 448.2 456.269 458.2 ;
    END
  END AVDD_IO
  PIN scan_in[24]
    DIRECTION INPUT ;
    USE SIGNAL ;
    PORT
      LAYER M5 ;
        RECT 280.28 539.8 280.36 540 ;
    END
  END scan_in[24]
  PIN AVDD_IO_HV
    DIRECTION INOUT ;
    USE POWER ;
    PORT
      CLASS BUMP ;
      LAYER AP ;
        RECT 266.269 88.2 276.269 98.2 ;
    END
  END AVDD_IO_HV
  PIN scan_in[26]
    DIRECTION INPUT ;
    USE SIGNAL ;
    PORT
      LAYER M5 ;
        RECT 280.6 539.8 280.68 540 ;
    END
  END scan_in[26]
  PIN scan_in[28]
    DIRECTION INPUT ;
    USE SIGNAL ;
    PORT
      LAYER M5 ;
        RECT 280.92 539.8 281 540 ;
    END
  END scan_in[28]
  PIN scan_in[30]
    DIRECTION INPUT ;
    USE SIGNAL ;
    PORT
      LAYER M5 ;
        RECT 281.24 539.8 281.32 540 ;
    END
  END scan_in[30]
  PIN scan_in[32]
    DIRECTION INPUT ;
    USE SIGNAL ;
    PORT
      LAYER M5 ;
        RECT 281.56 539.8 281.64 540 ;
    END
  END scan_in[32]
  PIN scan_in[33]
    DIRECTION INPUT ;
    USE SIGNAL ;
    PORT
      LAYER M5 ;
        RECT 281.72 539.8 281.8 540 ;
    END
  END scan_in[33]
  PIN scan_ats_hssiclock
    DIRECTION OUTPUT ;
    USE SIGNAL ;
    PORT
      LAYER M5 ;
        RECT 264.12 539.8 264.2 540 ;
    END
  END scan_ats_hssiclock
  PIN apb_pslverr
    DIRECTION OUTPUT ;
    USE SIGNAL ;
    PORT
      LAYER M5 ;
        RECT 295.4 539.8 295.48 540 ;
    END
  END apb_pslverr
  PIN usb2_phy_spare_out[0]
    DIRECTION OUTPUT ;
    USE SIGNAL ;
    PORT
      LAYER M5 ;
        RECT 339.48 539.8 339.56 540 ;
    END
  END usb2_phy_spare_out[0]
  PIN usb2_phy_spare_out[2]
    DIRECTION OUTPUT ;
    USE SIGNAL ;
    PORT
      LAYER M5 ;
        RECT 339.8 539.8 339.88 540 ;
    END
  END usb2_phy_spare_out[2]
  PIN usb2_phy_spare_out[4]
    DIRECTION OUTPUT ;
    USE SIGNAL ;
    PORT
      LAYER M5 ;
        RECT 340.12 539.8 340.2 540 ;
    END
  END usb2_phy_spare_out[4]
  PIN RTRIM
    DIRECTION INOUT ;
    USE ANALOG ;
    PORT
      CLASS BUMP ;
      LAYER AP ;
        RECT 86.269 268.2 96.269 278.2 ;
    END
  END RTRIM
  PIN usb2_phy_arch[1]
    DIRECTION INPUT ;
    USE SIGNAL ;
    PORT
      LAYER M5 ;
        RECT 318.12 539.8 318.2 540 ;
    END
  END usb2_phy_arch[1]
  PIN pso_disable_sel[1]
    DIRECTION INPUT ;
    USE SIGNAL ;
    PORT
      LAYER M5 ;
        RECT 304.76 539.8 304.84 540 ;
    END
  END pso_disable_sel[1]
  PIN hssi_ted_en
    DIRECTION INPUT ;
    USE SIGNAL ;
    PORT
      LAYER M5 ;
        RECT 323.56 539.8 323.64 540 ;
    END
  END hssi_ted_en
  PIN txvalidh
    DIRECTION INPUT ;
    USE SIGNAL ;
    PORT
      LAYER M5 ;
        RECT 308.76 539.8 308.84 540 ;
    END
  END txvalidh
  PIN xcvrselect[0]
    DIRECTION INPUT ;
    USE SIGNAL ;
    PORT
      LAYER M5 ;
        RECT 323.08 539.8 323.16 540 ;
    END
  END xcvrselect[0]
  PIN scan_out[15]
    DIRECTION OUTPUT ;
    USE SIGNAL ;
    PORT
      LAYER M5 ;
        RECT 343.16 539.8 343.24 540 ;
    END
  END scan_out[15]
  PIN powerdown[0]
    DIRECTION INPUT ;
    USE SIGNAL ;
    PORT
      LAYER M5 ;
        RECT 319.72 539.8 319.8 540 ;
    END
  END powerdown[0]
  PIN hssi_txvalid[0]
    DIRECTION INPUT ;
    USE SIGNAL ;
    PORT
      LAYER M5 ;
        RECT 323.88 539.8 323.96 540 ;
    END
  END hssi_txvalid[0]
  PIN txbitstuffenableh
    DIRECTION INPUT ;
    USE SIGNAL ;
    PORT
      LAYER M5 ;
        RECT 320.2 539.8 320.28 540 ;
    END
  END txbitstuffenableh
  PIN dmpulldown
    DIRECTION INPUT ;
    USE SIGNAL ;
    PORT
      LAYER M5 ;
        RECT 322.6 539.8 322.68 540 ;
    END
  END dmpulldown
  PIN databus16_8
    DIRECTION INPUT ;
    USE SIGNAL ;
    PORT
      LAYER M5 ;
        RECT 320.36 539.8 320.44 540 ;
    END
  END databus16_8
  PIN sleepm
    DIRECTION INPUT ;
    USE SIGNAL ;
    PORT
      LAYER M5 ;
        RECT 309.24 539.8 309.32 540 ;
    END
  END sleepm
  PIN scan_in[0]
    DIRECTION INPUT ;
    USE SIGNAL ;
    PORT
      LAYER M5 ;
        RECT 276.44 539.8 276.52 540 ;
    END
  END scan_in[0]
  PIN scan_in[2]
    DIRECTION INPUT ;
    USE SIGNAL ;
    PORT
      LAYER M5 ;
        RECT 276.76 539.8 276.84 540 ;
    END
  END scan_in[2]
  PIN scan_in[4]
    DIRECTION INPUT ;
    USE SIGNAL ;
    PORT
      LAYER M5 ;
        RECT 277.08 539.8 277.16 540 ;
    END
  END scan_in[4]
  PIN hssi_datain[0]
    DIRECTION INPUT ;
    USE SIGNAL ;
    PORT
      LAYER M5 ;
        RECT 291.24 539.8 291.32 540 ;
    END
  END hssi_datain[0]
  PIN hssi_mode
    DIRECTION INPUT ;
    USE SIGNAL ;
    PORT
      LAYER M5 ;
        RECT 319.08 539.8 319.16 540 ;
    END
  END hssi_mode
  PIN scan_in[25]
    DIRECTION INPUT ;
    USE SIGNAL ;
    PORT
      LAYER M5 ;
        RECT 280.44 539.8 280.52 540 ;
    END
  END scan_in[25]
  PIN bist_error_count[1]
    DIRECTION OUTPUT ;
    USE SIGNAL ;
    PORT
      LAYER M5 ;
        RECT 338.36 539.8 338.44 540 ;
    END
  END bist_error_count[1]
  PIN scan_hssiclock
    DIRECTION INPUT ;
    USE SIGNAL ;
    PORT
      LAYER M5 ;
        RECT 263.8 539.8 263.88 540 ;
    END
  END scan_hssiclock
  PIN scan_in[10]
    DIRECTION INPUT ;
    USE SIGNAL ;
    PORT
      LAYER M5 ;
        RECT 278.04 539.8 278.12 540 ;
    END
  END scan_in[10]
  PIN scan_in[8]
    DIRECTION INPUT ;
    USE SIGNAL ;
    PORT
      LAYER M5 ;
        RECT 277.72 539.8 277.8 540 ;
    END
  END scan_in[8]
  PIN loopback[1]
    DIRECTION INPUT ;
    USE SIGNAL ;
    PORT
      LAYER M5 ;
        RECT 324.84 539.8 324.92 540 ;
    END
  END loopback[1]
  PIN reset
    DIRECTION INPUT ;
    USE SIGNAL ;
    PORT
      LAYER M5 ;
        RECT 321 539.8 321.08 540 ;
    END
  END reset
  PIN bist_mode_sel[2]
    DIRECTION INPUT ;
    USE SIGNAL ;
    PORT
      LAYER M5 ;
        RECT 333.4 539.8 333.48 540 ;
    END
  END bist_mode_sel[2]
  PIN lane_reverse
    DIRECTION INPUT ;
    USE SIGNAL ;
    PORT
      LAYER M5 ;
        RECT 324.04 539.8 324.12 540 ;
    END
  END lane_reverse
  PIN bist_mode_en
    DIRECTION INPUT ;
    USE SIGNAL ;
    PORT
      LAYER M5 ;
        RECT 307.8 539.8 307.88 540 ;
    END
  END bist_mode_en
  PIN vdm_src_en
    DIRECTION INPUT ;
    USE SIGNAL ;
    PORT
      LAYER M5 ;
        RECT 310.2 539.8 310.28 540 ;
    END
  END vdm_src_en
  PIN rid_float_comp_en
    DIRECTION INPUT ;
    USE SIGNAL ;
    PORT
      LAYER M5 ;
        RECT 310.36 539.8 310.44 540 ;
    END
  END rid_float_comp_en
  PIN idp_sink_en
    DIRECTION INPUT ;
    USE SIGNAL ;
    PORT
      LAYER M5 ;
        RECT 310.68 539.8 310.76 540 ;
    END
  END idp_sink_en
  PIN bist_error_count[7]
    DIRECTION OUTPUT ;
    USE SIGNAL ;
    PORT
      LAYER M5 ;
        RECT 339.32 539.8 339.4 540 ;
    END
  END bist_error_count[7]
  PIN scan_in[27]
    DIRECTION INPUT ;
    USE SIGNAL ;
    PORT
      LAYER M5 ;
        RECT 280.76 539.8 280.84 540 ;
    END
  END scan_in[27]
  PIN bist_error_count[5]
    DIRECTION OUTPUT ;
    USE SIGNAL ;
    PORT
      LAYER M5 ;
        RECT 339 539.8 339.08 540 ;
    END
  END bist_error_count[5]
  PIN bist_error_count[3]
    DIRECTION OUTPUT ;
    USE SIGNAL ;
    PORT
      LAYER M5 ;
        RECT 338.68 539.8 338.76 540 ;
    END
  END bist_error_count[3]
  PIN scan_in[29]
    DIRECTION INPUT ;
    USE SIGNAL ;
    PORT
      LAYER M5 ;
        RECT 281.08 539.8 281.16 540 ;
    END
  END scan_in[29]
  PIN scan_in[31]
    DIRECTION INPUT ;
    USE SIGNAL ;
    PORT
      LAYER M5 ;
        RECT 281.4 539.8 281.48 540 ;
    END
  END scan_in[31]
  PIN datain[10]
    DIRECTION INPUT ;
    USE SIGNAL ;
    PORT
      LAYER M5 ;
        RECT 293 539.8 293.08 540 ;
    END
  END datain[10]
  PIN pll_clkon
    DIRECTION INPUT ;
    USE SIGNAL ;
    PORT
      LAYER M5 ;
        RECT 264.44 539.8 264.52 540 ;
    END
  END pll_clkon
  PIN datain[12]
    DIRECTION INPUT ;
    USE SIGNAL ;
    PORT
      LAYER M5 ;
        RECT 293.32 539.8 293.4 540 ;
    END
  END datain[12]
  PIN opmode[0]
    DIRECTION INPUT ;
    USE SIGNAL ;
    PORT
      LAYER M5 ;
        RECT 320.04 539.8 320.12 540 ;
    END
  END opmode[0]
  PIN tap_tdo
    DIRECTION OUTPUT ;
    USE SIGNAL ;
    PORT
      LAYER M5 ;
        RECT 344.76 539.8 344.84 540 ;
    END
  END tap_tdo
  PIN adp_sense_en
    DIRECTION INPUT ;
    USE SIGNAL ;
    PORT
      LAYER M5 ;
        RECT 311.48 539.8 311.56 540 ;
    END
  END adp_sense_en
  PIN apb_prdata[1]
    DIRECTION OUTPUT ;
    USE SIGNAL ;
    PORT
      LAYER M5 ;
        RECT 343.64 539.8 343.72 540 ;
    END
  END apb_prdata[1]
  PIN adp_probe_en
    DIRECTION INPUT ;
    USE SIGNAL ;
    PORT
      LAYER M5 ;
        RECT 311.8 539.8 311.88 540 ;
    END
  END adp_probe_en
  PIN apb_prdata[3]
    DIRECTION OUTPUT ;
    USE SIGNAL ;
    PORT
      LAYER M5 ;
        RECT 343.96 539.8 344.04 540 ;
    END
  END apb_prdata[3]
  PIN apb_prdata[5]
    DIRECTION OUTPUT ;
    USE SIGNAL ;
    PORT
      LAYER M5 ;
        RECT 344.28 539.8 344.36 540 ;
    END
  END apb_prdata[5]
  PIN vbus_sel[0]
    DIRECTION INPUT ;
    USE SIGNAL ;
    PORT
      LAYER M5 ;
        RECT 321.16 539.8 321.24 540 ;
    END
  END vbus_sel[0]
  PIN apb_prdata[7]
    DIRECTION OUTPUT ;
    USE SIGNAL ;
    PORT
      LAYER M5 ;
        RECT 344.6 539.8 344.68 540 ;
    END
  END apb_prdata[7]
  PIN pllrefsel[0]
    DIRECTION INPUT ;
    USE SIGNAL ;
    PORT
      LAYER M5 ;
        RECT 322.12 539.8 322.2 540 ;
    END
  END pllrefsel[0]
  PIN AVDD_CORE
    DIRECTION INOUT ;
    USE POWER ;
    PORT
      CLASS BUMP ;
      LAYER AP ;
        RECT 266.269 448.2 276.269 458.2 ;
    END
  END AVDD_CORE
  PIN apb_paddr[5]
    DIRECTION INPUT ;
    USE SIGNAL ;
    PORT
      LAYER M5 ;
        RECT 332.12 539.8 332.2 540 ;
    END
  END apb_paddr[5]
  PIN DM
    DIRECTION INOUT ;
    USE ANALOG ;
    PORT
      CLASS BUMP ;
      LAYER AP ;
        RECT 446.269 88.2 456.269 98.2 ;
    END
  END DM
  PIN apb_paddr[7]
    DIRECTION INPUT ;
    USE SIGNAL ;
    PORT
      LAYER M5 ;
        RECT 331.8 539.8 331.88 540 ;
    END
  END apb_paddr[7]
  PIN DP
    DIRECTION INOUT ;
    USE ANALOG ;
    PORT
      CLASS BUMP ;
      LAYER AP ;
        RECT 446.269 268.2 456.269 278.2 ;
    END
  END DP
  PIN apb_pselx
    DIRECTION INPUT ;
    USE SIGNAL ;
    PORT
      LAYER M5 ;
        RECT 309.88 539.8 309.96 540 ;
    END
  END apb_pselx
  PIN ID
    DIRECTION INOUT ;
    USE ANALOG ;
    PORT
      CLASS BUMP ;
      LAYER AP ;
        RECT 86.269 88.2 96.269 98.2 ;
    END
  END ID
  PIN apb_pwrite
    DIRECTION INPUT ;
    USE SIGNAL ;
    PORT
      LAYER M5 ;
        RECT 307.48 539.8 307.56 540 ;
    END
  END apb_pwrite
  PIN usb2_phy_spare_in[1]
    DIRECTION INPUT ;
    USE SIGNAL ;
    PORT
      LAYER M5 ;
        RECT 294.12 539.8 294.2 540 ;
    END
  END usb2_phy_spare_in[1]
  PIN scan_in[6]
    DIRECTION INPUT ;
    USE SIGNAL ;
    PORT
      LAYER M5 ;
        RECT 277.4 539.8 277.48 540 ;
    END
  END scan_in[6]
  PIN usb2_phy_spare_in[3]
    DIRECTION INPUT ;
    USE SIGNAL ;
    PORT
      LAYER M5 ;
        RECT 294.44 539.8 294.52 540 ;
    END
  END usb2_phy_spare_in[3]
  PIN pllrefsel[2]
    DIRECTION INPUT ;
    USE SIGNAL ;
    PORT
      LAYER M5 ;
        RECT 321.96 539.8 322.04 540 ;
    END
  END pllrefsel[2]
  PIN scan_in[12]
    DIRECTION INPUT ;
    USE SIGNAL ;
    PORT
      LAYER M5 ;
        RECT 278.36 539.8 278.44 540 ;
    END
  END scan_in[12]
  PIN usb2_phy_spare_in[5]
    DIRECTION INPUT ;
    USE SIGNAL ;
    PORT
      LAYER M5 ;
        RECT 294.76 539.8 294.84 540 ;
    END
  END usb2_phy_spare_in[5]
  PIN psm_rstn
    DIRECTION INPUT ;
    USE SIGNAL ;
    PORT
      LAYER M5 ;
        RECT 309.56 539.8 309.64 540 ;
    END
  END psm_rstn
  PIN usb2_phy_spare_in[7]
    DIRECTION INPUT ;
    USE SIGNAL ;
    PORT
      LAYER M5 ;
        RECT 295.08 539.8 295.16 540 ;
    END
  END usb2_phy_spare_in[7]
  PIN scan_out[19]
    DIRECTION OUTPUT ;
    USE SIGNAL ;
    PORT
      LAYER M5 ;
        RECT 352.6 539.8 352.68 540 ;
    END
  END scan_out[19]
  PIN scan_out[30]
    DIRECTION OUTPUT ;
    USE SIGNAL ;
    PORT
      LAYER M5 ;
        RECT 354.36 539.8 354.44 540 ;
    END
  END scan_out[30]
  PIN scan_out[24]
    DIRECTION OUTPUT ;
    USE SIGNAL ;
    PORT
      LAYER M5 ;
        RECT 353.4 539.8 353.48 540 ;
    END
  END scan_out[24]
  PIN scan_out[26]
    DIRECTION OUTPUT ;
    USE SIGNAL ;
    PORT
      LAYER M5 ;
        RECT 353.72 539.8 353.8 540 ;
    END
  END scan_out[26]
  PIN scan_out[17]
    DIRECTION OUTPUT ;
    USE SIGNAL ;
    PORT
      LAYER M5 ;
        RECT 352.28 539.8 352.36 540 ;
    END
  END scan_out[17]
  PIN scan_out[32]
    DIRECTION OUTPUT ;
    USE SIGNAL ;
    PORT
      LAYER M5 ;
        RECT 354.68 539.8 354.76 540 ;
    END
  END scan_out[32]
  PIN scan_in[23]
    DIRECTION INPUT ;
    USE SIGNAL ;
    PORT
      LAYER M5 ;
        RECT 280.12 539.8 280.2 540 ;
    END
  END scan_in[23]
  PIN scan_out[34]
    DIRECTION OUTPUT ;
    USE SIGNAL ;
    PORT
      LAYER M5 ;
        RECT 355 539.8 355.08 540 ;
    END
  END scan_out[34]
  PIN scan_out[28]
    DIRECTION OUTPUT ;
    USE SIGNAL ;
    PORT
      LAYER M5 ;
        RECT 354.04 539.8 354.12 540 ;
    END
  END scan_out[28]
  PIN scan_out[21]
    DIRECTION OUTPUT ;
    USE SIGNAL ;
    PORT
      LAYER M5 ;
        RECT 352.92 539.8 353 540 ;
    END
  END scan_out[21]
  PIN scan_in[21]
    DIRECTION INPUT ;
    USE SIGNAL ;
    PORT
      LAYER M5 ;
        RECT 279.8 539.8 279.88 540 ;
    END
  END scan_in[21]
  PIN scan_in[19]
    DIRECTION INPUT ;
    USE SIGNAL ;
    PORT
      LAYER M5 ;
        RECT 279.48 539.8 279.56 540 ;
    END
  END scan_in[19]
  PIN dataout[3]
    DIRECTION OUTPUT ;
    USE SIGNAL ;
    PORT
      LAYER M5 ;
        RECT 335.48 539.8 335.56 540 ;
    END
  END dataout[3]
  PIN dataout[5]
    DIRECTION OUTPUT ;
    USE SIGNAL ;
    PORT
      LAYER M5 ;
        RECT 335.8 539.8 335.88 540 ;
    END
  END dataout[5]
  PIN dataout[7]
    DIRECTION OUTPUT ;
    USE SIGNAL ;
    PORT
      LAYER M5 ;
        RECT 336.12 539.8 336.2 540 ;
    END
  END dataout[7]
  PIN apb_paddr[3]
    DIRECTION INPUT ;
    USE SIGNAL ;
    PORT
      LAYER M5 ;
        RECT 332.44 539.8 332.52 540 ;
    END
  END apb_paddr[3]
  PIN scan_in[16]
    DIRECTION INPUT ;
    USE SIGNAL ;
    PORT
      LAYER M5 ;
        RECT 279 539.8 279.08 540 ;
    END
  END scan_in[16]
  PIN adp_source_current_en
    DIRECTION INPUT ;
    USE SIGNAL ;
    PORT
      LAYER M5 ;
        RECT 311.16 539.8 311.24 540 ;
    END
  END adp_source_current_en
  PIN DVDD_CORE
    DIRECTION INOUT ;
    USE POWER ;
    PORT
      LAYER M11 ;
        RECT 274.09 539.8 275.58 540 ;
    END
    PORT
      LAYER M10 ;
        RECT 274.09 539.8 275.58 540 ;
    END
    PORT
      LAYER M11 ;
        RECT 281 539.8 282.49 540 ;
    END
    PORT
      LAYER M10 ;
        RECT 281 539.8 282.49 540 ;
    END
    PORT
      LAYER M11 ;
        RECT 290.999 539.8 292.489 540 ;
    END
    PORT
      LAYER M10 ;
        RECT 290.999 539.8 292.489 540 ;
    END
    PORT
      LAYER M11 ;
        RECT 301.001 539.8 302.491 540 ;
    END
    PORT
      LAYER M10 ;
        RECT 301.001 539.8 302.491 540 ;
    END
    PORT
      LAYER M11 ;
        RECT 310.999 539.8 312.489 540 ;
    END
    PORT
      LAYER M10 ;
        RECT 310.999 539.8 312.489 540 ;
    END
    PORT
      LAYER M11 ;
        RECT 321 539.8 322.49 540 ;
    END
    PORT
      LAYER M10 ;
        RECT 321 539.8 322.49 540 ;
    END
    PORT
      LAYER M11 ;
        RECT 331 539.8 332.49 540 ;
    END
    PORT
      LAYER M10 ;
        RECT 331 539.8 332.49 540 ;
    END
  END DVDD_CORE
  PIN xcvrselect[1]
    DIRECTION INPUT ;
    USE SIGNAL ;
    PORT
      LAYER M5 ;
        RECT 322.92 539.8 323 540 ;
    END
  END xcvrselect[1]
  PIN opmode[1]
    DIRECTION INPUT ;
    USE SIGNAL ;
    PORT
      LAYER M5 ;
        RECT 319.88 539.8 319.96 540 ;
    END
  END opmode[1]
  PIN powerdown[1]
    DIRECTION INPUT ;
    USE SIGNAL ;
    PORT
      LAYER M5 ;
        RECT 319.56 539.8 319.64 540 ;
    END
  END powerdown[1]
  PIN txbitstuffenable
    DIRECTION INPUT ;
    USE SIGNAL ;
    PORT
      LAYER M5 ;
        RECT 308.92 539.8 309 540 ;
    END
  END txbitstuffenable
  PIN dppulldown
    DIRECTION INPUT ;
    USE SIGNAL ;
    PORT
      LAYER M5 ;
        RECT 322.44 539.8 322.52 540 ;
    END
  END dppulldown
  PIN termselect
    DIRECTION INPUT ;
    USE SIGNAL ;
    PORT
      LAYER M5 ;
        RECT 309.08 539.8 309.16 540 ;
    END
  END termselect
  PIN suspendm
    DIRECTION INPUT ;
    USE SIGNAL ;
    PORT
      LAYER M5 ;
        RECT 320.52 539.8 320.6 540 ;
    END
  END suspendm
  PIN scan_in[1]
    DIRECTION INPUT ;
    USE SIGNAL ;
    PORT
      LAYER M5 ;
        RECT 276.6 539.8 276.68 540 ;
    END
  END scan_in[1]
  PIN scan_in[3]
    DIRECTION INPUT ;
    USE SIGNAL ;
    PORT
      LAYER M5 ;
        RECT 276.92 539.8 277 540 ;
    END
  END scan_in[3]
  PIN scan_in[5]
    DIRECTION INPUT ;
    USE SIGNAL ;
    PORT
      LAYER M5 ;
        RECT 277.24 539.8 277.32 540 ;
    END
  END scan_in[5]
  PIN scan_in[7]
    DIRECTION INPUT ;
    USE SIGNAL ;
    PORT
      LAYER M5 ;
        RECT 277.56 539.8 277.64 540 ;
    END
  END scan_in[7]
  PIN scan_in[9]
    DIRECTION INPUT ;
    USE SIGNAL ;
    PORT
      LAYER M5 ;
        RECT 277.88 539.8 277.96 540 ;
    END
  END scan_in[9]
  PIN scan_in[11]
    DIRECTION INPUT ;
    USE SIGNAL ;
    PORT
      LAYER M5 ;
        RECT 278.2 539.8 278.28 540 ;
    END
  END scan_in[11]
  PIN scan_in[13]
    DIRECTION INPUT ;
    USE SIGNAL ;
    PORT
      LAYER M5 ;
        RECT 278.52 539.8 278.6 540 ;
    END
  END scan_in[13]
  PIN scan_ats_mode
    DIRECTION INPUT ;
    USE SIGNAL ;
    PORT
      LAYER M5 ;
        RECT 320.68 539.8 320.76 540 ;
    END
  END scan_ats_mode
  PIN scan_mode
    DIRECTION INPUT ;
    USE SIGNAL ;
    PORT
      LAYER M5 ;
        RECT 320.84 539.8 320.92 540 ;
    END
  END scan_mode
  OBS
    LAYER M1 SPACING 0.032 ;
      RECT 0 0 540 540 ;
    LAYER M2 SPACING 0.032 ;
      RECT 0 0 540 540 ;
    LAYER M3 SPACING 0.032 ;
      RECT 0 0 540 540 ;
    LAYER M4 SPACING 0.04 ;
      RECT 0 0 540 540 ;
    LAYER M5 SPACING 0.04 ;
      POLYGON 540 540 355.12 540 355.12 539.76 352.24 539.76 352.24 540 345.36 540 345.36 539.76 331.76 539.76 331.76 540 325.76 540 325.76 539.76 317.92 539.76 317.92 540 311.92 540 311.92 539.76 303.92 539.76 303.92 540 297.12 540 297.12 539.76 291.04 539.76 291.04 540 282.16 540 282.16 539.76 276.4 539.76 276.4 540 269.36 540 269.36 539.76 269.2 539.76 269.2 540 269.04 540 269.04 539.76 268.88 539.76 268.88 540 268.72 540 268.72 539.76 268.56 539.76 268.56 540 268.4 540 268.4 539.76 268.24 539.76 268.24 540 268.08 540 268.08 539.76 267.92 539.76 267.92 540 267.76 540 267.76 539.76 267.6 539.76 267.6 540 267.44 540 267.44 539.76 267.28 539.76 267.28 540 267.12 540 267.12 539.76 266.96 539.76 266.96 540 266.8 540 266.8 539.76 266.64 539.76 266.64 540 266.48 540 266.48 539.76 266.32 539.76 266.32 540 266.16 540 266.16 539.76 266 539.76 266 540 265.84 540 265.84 539.76 265.68 539.76 265.68 540 265.52 540 265.52 539.76 265.36 539.76 265.36 540 265.2 540 265.2 539.76 265.04 539.76 265.04 540 264.88 540 264.88 539.76 264.72 539.76 264.72 540 264.56 540 264.56 539.76 264.4 539.76 264.4 540 264.24 540 264.24 539.76 264.08 539.76 264.08 540 263.92 540 263.92 539.76 263.76 539.76 263.76 540 0 540 0 0 540 0 ;
    LAYER M6 SPACING 0.04 ;
      RECT 0 0 540 540 ;
    LAYER M7 SPACING 0.04 ;
      RECT 0 0 540 540 ;
    LAYER M8 SPACING 0.064 ;
      RECT 0 0 540 540 ;
    LAYER M9 SPACING 0.064 ;
      RECT 0 0 540 540 ;
    LAYER M10 SPACING 0.45 ;
      POLYGON 540 540 355.291 540 355.291 539.35 351.891 539.35 351.891 540 336.03 540 336.03 539.35 333.64 539.35 333.64 540 332.94 540 332.94 539.35 330.55 539.35 330.55 540 326.031 540 326.031 539.35 323.641 539.35 323.641 540 322.94 540 322.94 539.35 320.55 539.35 320.55 540 316.03 540 316.03 539.35 313.64 539.35 313.64 540 312.939 540 312.939 539.35 310.549 539.35 310.549 540 306.032 540 306.032 539.35 303.642 539.35 303.642 540 302.941 540 302.941 539.35 300.551 539.35 300.551 540 296.03 540 296.03 539.35 293.64 539.35 293.64 540 292.939 540 292.939 539.35 290.549 539.35 290.549 540 286.03 540 286.03 539.35 283.64 539.35 283.64 540 282.94 540 282.94 539.35 280.55 539.35 280.55 540 276.03 540 276.03 539.35 273.64 539.35 273.64 540 272.94 540 272.94 539.35 270.55 539.35 270.55 540 256.791 540 256.791 539.35 253.391 539.35 253.391 540 0 540 0 0 540 0 ;
    LAYER M11 SPACING 0.45 ;
      POLYGON 540 540 355.291 540 355.291 539.35 351.891 539.35 351.891 540 336.03 540 336.03 539.35 333.64 539.35 333.64 540 332.94 540 332.94 539.35 330.55 539.35 330.55 540 326.031 540 326.031 539.35 323.641 539.35 323.641 540 322.94 540 322.94 539.35 320.55 539.35 320.55 540 316.03 540 316.03 539.35 313.64 539.35 313.64 540 312.939 540 312.939 539.35 310.549 539.35 310.549 540 306.032 540 306.032 539.35 303.642 539.35 303.642 540 302.941 540 302.941 539.35 300.551 539.35 300.551 540 296.03 540 296.03 539.35 293.64 539.35 293.64 540 292.939 540 292.939 539.35 290.549 539.35 290.549 540 286.03 540 286.03 539.35 283.64 539.35 283.64 540 282.94 540 282.94 539.35 280.55 539.35 280.55 540 276.03 540 276.03 539.35 273.64 539.35 273.64 540 272.94 540 272.94 539.35 270.55 539.35 270.55 540 256.791 540 256.791 539.35 253.391 539.35 253.391 540 0 540 0 0 540 0 ;
    LAYER AP SPACING 1.8 ;
      POLYGON 540 82.176 537.2 82.176 537.2 97.776 540 97.776 540 262.176 537.2 262.176 537.2 277.776 540 277.776 540 442.176 537.2 442.176 537.2 457.776 540 457.776 540 540 458.069 540 458.069 86.4 444.469 86.4 444.469 100 458.069 100 458.069 266.4 444.469 266.4 444.469 280 458.069 280 458.069 446.4 444.469 446.4 444.469 460 458.069 460 458.069 540 278.069 540 278.069 86.4 264.469 86.4 264.469 100 278.069 100 278.069 266.4 264.469 266.4 264.469 280 278.069 280 278.069 446.4 264.469 446.4 264.469 460 278.069 460 278.069 540 98.069 540 98.069 86.4 84.469 86.4 84.469 100 98.069 100 98.069 266.4 84.469 266.4 84.469 280 98.069 280 98.069 446.4 84.469 446.4 84.469 460 98.069 460 98.069 540 0 540 0 457.776 2.8 457.776 2.8 442.176 0 442.176 0 277.776 2.8 277.776 2.8 262.176 0 262.176 0 97.776 2.8 97.776 2.8 82.176 0 82.176 0 0 540 0 ;
  END
END cdn_sd1000_t16ffc_01_vc176_2xa1xd3xe2y2r

END LIBRARY
